VERSION 5.4 ;
NAMESCASESENSITIVE ON ;
BUSBITCHARS "[]" ;
DIVIDERCHAR "/" ;
UNITS
  DATABASE MICRONS 2000 ;
END UNITS
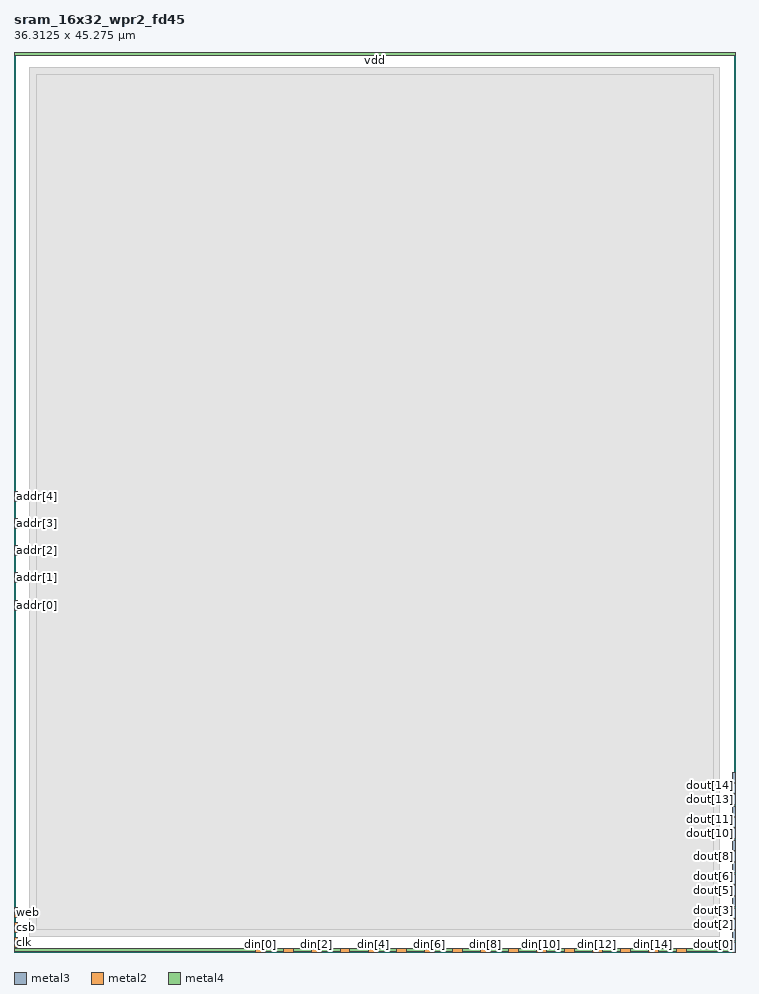
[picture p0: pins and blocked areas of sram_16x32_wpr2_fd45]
MACRO sram_16x32_wpr2_fd45
   CLASS BLOCK ;
   SIZE 36.3125 BY 45.2750 ;
   SYMMETRY X Y R90 ;
   PIN addr[0]
      DIRECTION INPUT ;
      PORT
         LAYER metal3 ;
         RECT 0.0000 17.2025 0.1600 17.7025 ;
      END
   END addr[0]
   PIN addr[1]
      DIRECTION INPUT ;
      PORT
         LAYER metal3 ;
         RECT 0.0000 18.5675 0.1600 19.0675 ;
      END
   END addr[1]
   PIN addr[2]
      DIRECTION INPUT ;
      PORT
         LAYER metal3 ;
         RECT 0.0000 19.9325 0.1600 20.4325 ;
      END
   END addr[2]
   PIN addr[3]
      DIRECTION INPUT ;
      PORT
         LAYER metal3 ;
         RECT 0.0000 21.2975 0.1600 21.7975 ;
      END
   END addr[3]
   PIN addr[4]
      DIRECTION INPUT ;
      PORT
         LAYER metal3 ;
         RECT 0.0000 22.6625 0.1600 23.1625 ;
      END
   END addr[4]
   PIN clk
      DIRECTION INPUT ;
      PORT
         LAYER metal2 ;
         RECT 0.0000 0.2425 0.1600 0.7425 ;
      END
   END clk
   PIN csb
      DIRECTION INPUT ;
      PORT
         LAYER metal2 ;
         RECT 0.0000 0.9925 0.1600 1.4925 ;
      END
   END csb
   PIN din[0]
      DIRECTION INPUT ;
      PORT
         LAYER metal2 ;
         RECT 12.1700 0.0000 12.6700 0.1600 ;
      END
   END din[0]
   PIN din[10]
      DIRECTION INPUT ;
      PORT
         LAYER metal2 ;
         RECT 26.2700 0.0000 26.7700 0.1600 ;
      END
   END din[10]
   PIN din[11]
      DIRECTION INPUT ;
      PORT
         LAYER metal2 ;
         RECT 27.6800 0.0000 28.1800 0.1600 ;
      END
   END din[11]
   PIN din[12]
      DIRECTION INPUT ;
      PORT
         LAYER metal2 ;
         RECT 29.0900 0.0000 29.5900 0.1600 ;
      END
   END din[12]
   PIN din[13]
      DIRECTION INPUT ;
      PORT
         LAYER metal2 ;
         RECT 30.5000 0.0000 31.0000 0.1600 ;
      END
   END din[13]
   PIN din[14]
      DIRECTION INPUT ;
      PORT
         LAYER metal2 ;
         RECT 31.9100 0.0000 32.4100 0.1600 ;
      END
   END din[14]
   PIN din[15]
      DIRECTION INPUT ;
      PORT
         LAYER metal2 ;
         RECT 33.3200 0.0000 33.8200 0.1600 ;
      END
   END din[15]
   PIN din[1]
      DIRECTION INPUT ;
      PORT
         LAYER metal2 ;
         RECT 13.5800 0.0000 14.0800 0.1600 ;
      END
   END din[1]
   PIN din[2]
      DIRECTION INPUT ;
      PORT
         LAYER metal2 ;
         RECT 14.9900 0.0000 15.4900 0.1600 ;
      END
   END din[2]
   PIN din[3]
      DIRECTION INPUT ;
      PORT
         LAYER metal2 ;
         RECT 16.4000 0.0000 16.9000 0.1600 ;
      END
   END din[3]
   PIN din[4]
      DIRECTION INPUT ;
      PORT
         LAYER metal2 ;
         RECT 17.8100 0.0000 18.3100 0.1600 ;
      END
   END din[4]
   PIN din[5]
      DIRECTION INPUT ;
      PORT
         LAYER metal2 ;
         RECT 19.2200 0.0000 19.7200 0.1600 ;
      END
   END din[5]
   PIN din[6]
      DIRECTION INPUT ;
      PORT
         LAYER metal2 ;
         RECT 20.6300 0.0000 21.1300 0.1600 ;
      END
   END din[6]
   PIN din[7]
      DIRECTION INPUT ;
      PORT
         LAYER metal2 ;
         RECT 22.0400 0.0000 22.5400 0.1600 ;
      END
   END din[7]
   PIN din[8]
      DIRECTION INPUT ;
      PORT
         LAYER metal2 ;
         RECT 23.4500 0.0000 23.9500 0.1600 ;
      END
   END din[8]
   PIN din[9]
      DIRECTION INPUT ;
      PORT
         LAYER metal2 ;
         RECT 24.8600 0.0000 25.3600 0.1600 ;
      END
   END din[9]
   PIN dout[0]
      DIRECTION OUTPUT ;
      PORT
         LAYER metal3 ;
         RECT 36.1525 0.0000 36.3125 0.5000 ;
      END
   END dout[0]
   PIN dout[10]
      DIRECTION OUTPUT ;
      PORT
         LAYER metal3 ;
         RECT 36.1525 5.7000 36.3125 6.2000 ;
      END
   END dout[10]
   PIN dout[11]
      DIRECTION OUTPUT ;
      PORT
         LAYER metal3 ;
         RECT 36.1525 6.2700 36.3125 6.7700 ;
      END
   END dout[11]
   PIN dout[12]
      DIRECTION OUTPUT ;
      PORT
         LAYER metal3 ;
         RECT 36.1525 6.8400 36.3125 7.3400 ;
      END
   END dout[12]
   PIN dout[13]
      DIRECTION OUTPUT ;
      PORT
         LAYER metal3 ;
         RECT 36.1525 7.4100 36.3125 7.9100 ;
      END
   END dout[13]
   PIN dout[14]
      DIRECTION OUTPUT ;
      PORT
         LAYER metal3 ;
         RECT 36.1525 7.9800 36.3125 8.4800 ;
      END
   END dout[14]
   PIN dout[15]
      DIRECTION OUTPUT ;
      PORT
         LAYER metal3 ;
         RECT 36.1525 8.5500 36.3125 9.0500 ;
      END
   END dout[15]
   PIN dout[1]
      DIRECTION OUTPUT ;
      PORT
         LAYER metal3 ;
         RECT 36.1525 0.5700 36.3125 1.0700 ;
      END
   END dout[1]
   PIN dout[2]
      DIRECTION OUTPUT ;
      PORT
         LAYER metal3 ;
         RECT 36.1525 1.1400 36.3125 1.6400 ;
      END
   END dout[2]
   PIN dout[3]
      DIRECTION OUTPUT ;
      PORT
         LAYER metal3 ;
         RECT 36.1525 1.7100 36.3125 2.2100 ;
      END
   END dout[3]
   PIN dout[4]
      DIRECTION OUTPUT ;
      PORT
         LAYER metal3 ;
         RECT 36.1525 2.2800 36.3125 2.7800 ;
      END
   END dout[4]
   PIN dout[5]
      DIRECTION OUTPUT ;
      PORT
         LAYER metal3 ;
         RECT 36.1525 2.8500 36.3125 3.3500 ;
      END
   END dout[5]
   PIN dout[6]
      DIRECTION OUTPUT ;
      PORT
         LAYER metal3 ;
         RECT 36.1525 3.4200 36.3125 3.9200 ;
      END
   END dout[6]
   PIN dout[7]
      DIRECTION OUTPUT ;
      PORT
         LAYER metal3 ;
         RECT 36.1525 3.9900 36.3125 4.4900 ;
      END
   END dout[7]
   PIN dout[8]
      DIRECTION OUTPUT ;
      PORT
         LAYER metal3 ;
         RECT 36.1525 4.5600 36.3125 5.0600 ;
      END
   END dout[8]
   PIN dout[9]
      DIRECTION OUTPUT ;
      PORT
         LAYER metal3 ;
         RECT 36.1525 5.1300 36.3125 5.6300 ;
      END
   END dout[9]
   PIN gnd
      DIRECTION INOUT ;
      USE GROUND ;
      SHAPE ABUTMENT ;
      PORT
         LAYER metal4 ;
         RECT 0.0000 0.0500 36.3125 0.2000 ;
      END
   END gnd
   PIN vdd
      DIRECTION INOUT ;
      USE POWER ;
      SHAPE ABUTMENT ;
      PORT
         LAYER metal4 ;
         RECT 0.0000 45.0750 36.3125 45.2250 ;
      END
   END vdd
   PIN web
      DIRECTION INPUT ;
      PORT
         LAYER metal2 ;
         RECT 0.0000 1.7425 0.1600 2.2425 ;
      END
   END web
   OBS
      LAYER metal1 ;
         RECT 0.8000 0.8000 35.5125 44.4750 ;
      LAYER metal2 ;
         RECT 0.8000 0.8000 35.5125 44.4750 ;
      LAYER metal3 ;
         RECT 0.8000 0.8000 35.5125 44.4750 ;
      LAYER metal4 ;
         RECT 1.1200 1.1200 35.1925 44.1550 ;
   END
END sram_16x32_wpr2_fd45
END LIBRARY
